VERSION 5.8 ;
BUSBITCHARS "[]" ;
DIVIDERCHAR "/" ;
UNITS
    DATABASE MICRONS 1000 ;
END UNITS

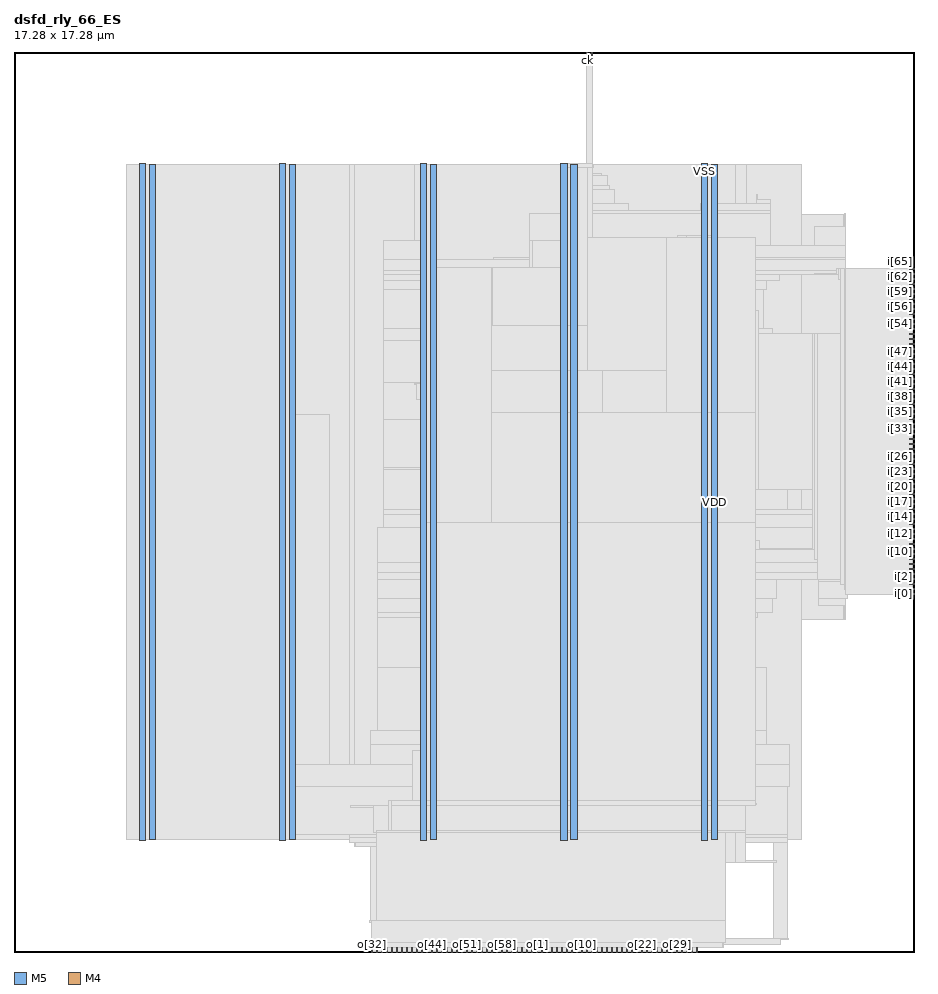
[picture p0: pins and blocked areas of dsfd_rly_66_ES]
MACRO dsfd_rly_66_ES
  FOREIGN dsfd_rly_66_ES 0 0 ;
  CLASS BLOCK ;
  SIZE 17.28 BY 17.28 ;
  PIN ck
    DIRECTION INPUT ;
    USE SIGNAL ;
    PORT
      LAYER M5 ;
        RECT  10.992 17.196 11.016 17.28 ;
    END
  END ck
  PIN i[0]
    DIRECTION INPUT ;
    USE SIGNAL ;
    PORT
      LAYER M4 ;
        RECT  17.196 6.864 17.28 6.888 ;
    END
  END i[0]
  PIN i[10]
    DIRECTION INPUT ;
    USE SIGNAL ;
    PORT
      LAYER M4 ;
        RECT  17.196 7.824 17.28 7.848 ;
    END
  END i[10]
  PIN i[11]
    DIRECTION INPUT ;
    USE SIGNAL ;
    PORT
      LAYER M4 ;
        RECT  17.196 7.92 17.28 7.944 ;
    END
  END i[11]
  PIN i[12]
    DIRECTION INPUT ;
    USE SIGNAL ;
    PORT
      LAYER M4 ;
        RECT  17.196 8.016 17.28 8.04 ;
    END
  END i[12]
  PIN i[13]
    DIRECTION INPUT ;
    USE SIGNAL ;
    PORT
      LAYER M4 ;
        RECT  17.196 8.112 17.28 8.136 ;
    END
  END i[13]
  PIN i[14]
    DIRECTION INPUT ;
    USE SIGNAL ;
    PORT
      LAYER M4 ;
        RECT  17.196 8.208 17.28 8.232 ;
    END
  END i[14]
  PIN i[15]
    DIRECTION INPUT ;
    USE SIGNAL ;
    PORT
      LAYER M4 ;
        RECT  17.196 8.304 17.28 8.328 ;
    END
  END i[15]
  PIN i[16]
    DIRECTION INPUT ;
    USE SIGNAL ;
    PORT
      LAYER M4 ;
        RECT  17.196 8.4 17.28 8.424 ;
    END
  END i[16]
  PIN i[17]
    DIRECTION INPUT ;
    USE SIGNAL ;
    PORT
      LAYER M4 ;
        RECT  17.196 8.496 17.28 8.52 ;
    END
  END i[17]
  PIN i[18]
    DIRECTION INPUT ;
    USE SIGNAL ;
    PORT
      LAYER M4 ;
        RECT  17.196 8.592 17.28 8.616 ;
    END
  END i[18]
  PIN i[19]
    DIRECTION INPUT ;
    USE SIGNAL ;
    PORT
      LAYER M4 ;
        RECT  17.196 8.688 17.28 8.712 ;
    END
  END i[19]
  PIN i[1]
    DIRECTION INPUT ;
    USE SIGNAL ;
    PORT
      LAYER M4 ;
        RECT  17.196 6.96 17.28 6.984 ;
    END
  END i[1]
  PIN i[20]
    DIRECTION INPUT ;
    USE SIGNAL ;
    PORT
      LAYER M4 ;
        RECT  17.196 8.784 17.28 8.808 ;
    END
  END i[20]
  PIN i[21]
    DIRECTION INPUT ;
    USE SIGNAL ;
    PORT
      LAYER M4 ;
        RECT  17.196 8.88 17.28 8.904 ;
    END
  END i[21]
  PIN i[22]
    DIRECTION INPUT ;
    USE SIGNAL ;
    PORT
      LAYER M4 ;
        RECT  17.196 8.976 17.28 9 ;
    END
  END i[22]
  PIN i[23]
    DIRECTION INPUT ;
    USE SIGNAL ;
    PORT
      LAYER M4 ;
        RECT  17.196 9.072 17.28 9.096 ;
    END
  END i[23]
  PIN i[24]
    DIRECTION INPUT ;
    USE SIGNAL ;
    PORT
      LAYER M4 ;
        RECT  17.196 9.168 17.28 9.192 ;
    END
  END i[24]
  PIN i[25]
    DIRECTION INPUT ;
    USE SIGNAL ;
    PORT
      LAYER M4 ;
        RECT  17.196 9.264 17.28 9.288 ;
    END
  END i[25]
  PIN i[26]
    DIRECTION INPUT ;
    USE SIGNAL ;
    PORT
      LAYER M4 ;
        RECT  17.196 9.36 17.28 9.384 ;
    END
  END i[26]
  PIN i[27]
    DIRECTION INPUT ;
    USE SIGNAL ;
    PORT
      LAYER M4 ;
        RECT  17.196 9.456 17.28 9.48 ;
    END
  END i[27]
  PIN i[28]
    DIRECTION INPUT ;
    USE SIGNAL ;
    PORT
      LAYER M4 ;
        RECT  17.196 9.552 17.28 9.576 ;
    END
  END i[28]
  PIN i[29]
    DIRECTION INPUT ;
    USE SIGNAL ;
    PORT
      LAYER M4 ;
        RECT  17.196 9.648 17.28 9.672 ;
    END
  END i[29]
  PIN i[2]
    DIRECTION INPUT ;
    USE SIGNAL ;
    PORT
      LAYER M4 ;
        RECT  17.196 7.056 17.28 7.08 ;
    END
  END i[2]
  PIN i[30]
    DIRECTION INPUT ;
    USE SIGNAL ;
    PORT
      LAYER M4 ;
        RECT  17.196 9.744 17.28 9.768 ;
    END
  END i[30]
  PIN i[31]
    DIRECTION INPUT ;
    USE SIGNAL ;
    PORT
      LAYER M4 ;
        RECT  17.196 9.84 17.28 9.864 ;
    END
  END i[31]
  PIN i[32]
    DIRECTION INPUT ;
    USE SIGNAL ;
    PORT
      LAYER M4 ;
        RECT  17.196 9.936 17.28 9.96 ;
    END
  END i[32]
  PIN i[33]
    DIRECTION INPUT ;
    USE SIGNAL ;
    PORT
      LAYER M4 ;
        RECT  17.196 10.032 17.28 10.056 ;
    END
  END i[33]
  PIN i[34]
    DIRECTION INPUT ;
    USE SIGNAL ;
    PORT
      LAYER M4 ;
        RECT  17.196 10.128 17.28 10.152 ;
    END
  END i[34]
  PIN i[35]
    DIRECTION INPUT ;
    USE SIGNAL ;
    PORT
      LAYER M4 ;
        RECT  17.196 10.224 17.28 10.248 ;
    END
  END i[35]
  PIN i[36]
    DIRECTION INPUT ;
    USE SIGNAL ;
    PORT
      LAYER M4 ;
        RECT  17.196 10.32 17.28 10.344 ;
    END
  END i[36]
  PIN i[37]
    DIRECTION INPUT ;
    USE SIGNAL ;
    PORT
      LAYER M4 ;
        RECT  17.196 10.416 17.28 10.44 ;
    END
  END i[37]
  PIN i[38]
    DIRECTION INPUT ;
    USE SIGNAL ;
    PORT
      LAYER M4 ;
        RECT  17.196 10.512 17.28 10.536 ;
    END
  END i[38]
  PIN i[39]
    DIRECTION INPUT ;
    USE SIGNAL ;
    PORT
      LAYER M4 ;
        RECT  17.196 10.608 17.28 10.632 ;
    END
  END i[39]
  PIN i[3]
    DIRECTION INPUT ;
    USE SIGNAL ;
    PORT
      LAYER M4 ;
        RECT  17.196 7.152 17.28 7.176 ;
    END
  END i[3]
  PIN i[40]
    DIRECTION INPUT ;
    USE SIGNAL ;
    PORT
      LAYER M4 ;
        RECT  17.196 10.704 17.28 10.728 ;
    END
  END i[40]
  PIN i[41]
    DIRECTION INPUT ;
    USE SIGNAL ;
    PORT
      LAYER M4 ;
        RECT  17.196 10.8 17.28 10.824 ;
    END
  END i[41]
  PIN i[42]
    DIRECTION INPUT ;
    USE SIGNAL ;
    PORT
      LAYER M4 ;
        RECT  17.196 10.896 17.28 10.92 ;
    END
  END i[42]
  PIN i[43]
    DIRECTION INPUT ;
    USE SIGNAL ;
    PORT
      LAYER M4 ;
        RECT  17.196 10.992 17.28 11.016 ;
    END
  END i[43]
  PIN i[44]
    DIRECTION INPUT ;
    USE SIGNAL ;
    PORT
      LAYER M4 ;
        RECT  17.196 11.088 17.28 11.112 ;
    END
  END i[44]
  PIN i[45]
    DIRECTION INPUT ;
    USE SIGNAL ;
    PORT
      LAYER M4 ;
        RECT  17.196 11.184 17.28 11.208 ;
    END
  END i[45]
  PIN i[46]
    DIRECTION INPUT ;
    USE SIGNAL ;
    PORT
      LAYER M4 ;
        RECT  17.196 11.28 17.28 11.304 ;
    END
  END i[46]
  PIN i[47]
    DIRECTION INPUT ;
    USE SIGNAL ;
    PORT
      LAYER M4 ;
        RECT  17.196 11.376 17.28 11.4 ;
    END
  END i[47]
  PIN i[48]
    DIRECTION INPUT ;
    USE SIGNAL ;
    PORT
      LAYER M4 ;
        RECT  17.196 11.472 17.28 11.496 ;
    END
  END i[48]
  PIN i[49]
    DIRECTION INPUT ;
    USE SIGNAL ;
    PORT
      LAYER M4 ;
        RECT  17.196 11.568 17.28 11.592 ;
    END
  END i[49]
  PIN i[4]
    DIRECTION INPUT ;
    USE SIGNAL ;
    PORT
      LAYER M4 ;
        RECT  17.196 7.248 17.28 7.272 ;
    END
  END i[4]
  PIN i[50]
    DIRECTION INPUT ;
    USE SIGNAL ;
    PORT
      LAYER M4 ;
        RECT  17.196 11.664 17.28 11.688 ;
    END
  END i[50]
  PIN i[51]
    DIRECTION INPUT ;
    USE SIGNAL ;
    PORT
      LAYER M4 ;
        RECT  17.196 11.76 17.28 11.784 ;
    END
  END i[51]
  PIN i[52]
    DIRECTION INPUT ;
    USE SIGNAL ;
    PORT
      LAYER M4 ;
        RECT  17.196 11.856 17.28 11.88 ;
    END
  END i[52]
  PIN i[53]
    DIRECTION INPUT ;
    USE SIGNAL ;
    PORT
      LAYER M4 ;
        RECT  17.196 11.952 17.28 11.976 ;
    END
  END i[53]
  PIN i[54]
    DIRECTION INPUT ;
    USE SIGNAL ;
    PORT
      LAYER M4 ;
        RECT  17.196 12.048 17.28 12.072 ;
    END
  END i[54]
  PIN i[55]
    DIRECTION INPUT ;
    USE SIGNAL ;
    PORT
      LAYER M4 ;
        RECT  17.196 12.144 17.28 12.168 ;
    END
  END i[55]
  PIN i[56]
    DIRECTION INPUT ;
    USE SIGNAL ;
    PORT
      LAYER M4 ;
        RECT  17.196 12.24 17.28 12.264 ;
    END
  END i[56]
  PIN i[57]
    DIRECTION INPUT ;
    USE SIGNAL ;
    PORT
      LAYER M4 ;
        RECT  17.196 12.336 17.28 12.36 ;
    END
  END i[57]
  PIN i[58]
    DIRECTION INPUT ;
    USE SIGNAL ;
    PORT
      LAYER M4 ;
        RECT  17.196 12.432 17.28 12.456 ;
    END
  END i[58]
  PIN i[59]
    DIRECTION INPUT ;
    USE SIGNAL ;
    PORT
      LAYER M4 ;
        RECT  17.196 12.528 17.28 12.552 ;
    END
  END i[59]
  PIN i[5]
    DIRECTION INPUT ;
    USE SIGNAL ;
    PORT
      LAYER M4 ;
        RECT  17.196 7.344 17.28 7.368 ;
    END
  END i[5]
  PIN i[60]
    DIRECTION INPUT ;
    USE SIGNAL ;
    PORT
      LAYER M4 ;
        RECT  17.196 12.624 17.28 12.648 ;
    END
  END i[60]
  PIN i[61]
    DIRECTION INPUT ;
    USE SIGNAL ;
    PORT
      LAYER M4 ;
        RECT  17.196 12.72 17.28 12.744 ;
    END
  END i[61]
  PIN i[62]
    DIRECTION INPUT ;
    USE SIGNAL ;
    PORT
      LAYER M4 ;
        RECT  17.196 12.816 17.28 12.84 ;
    END
  END i[62]
  PIN i[63]
    DIRECTION INPUT ;
    USE SIGNAL ;
    PORT
      LAYER M4 ;
        RECT  17.196 12.912 17.28 12.936 ;
    END
  END i[63]
  PIN i[64]
    DIRECTION INPUT ;
    USE SIGNAL ;
    PORT
      LAYER M4 ;
        RECT  17.196 13.008 17.28 13.032 ;
    END
  END i[64]
  PIN i[65]
    DIRECTION INPUT ;
    USE SIGNAL ;
    PORT
      LAYER M4 ;
        RECT  17.196 13.104 17.28 13.128 ;
    END
  END i[65]
  PIN i[6]
    DIRECTION INPUT ;
    USE SIGNAL ;
    PORT
      LAYER M4 ;
        RECT  17.196 7.44 17.28 7.464 ;
    END
  END i[6]
  PIN i[7]
    DIRECTION INPUT ;
    USE SIGNAL ;
    PORT
      LAYER M4 ;
        RECT  17.196 7.536 17.28 7.56 ;
    END
  END i[7]
  PIN i[8]
    DIRECTION INPUT ;
    USE SIGNAL ;
    PORT
      LAYER M4 ;
        RECT  17.196 7.632 17.28 7.656 ;
    END
  END i[8]
  PIN i[9]
    DIRECTION INPUT ;
    USE SIGNAL ;
    PORT
      LAYER M4 ;
        RECT  17.196 7.728 17.28 7.752 ;
    END
  END i[9]
  PIN o[0]
    DIRECTION OUTPUT ;
    USE SIGNAL ;
    PORT
      LAYER M5 ;
        RECT  9.936 0 9.96 0.084 ;
    END
  END o[0]
  PIN o[10]
    DIRECTION OUTPUT ;
    USE SIGNAL ;
    PORT
      LAYER M5 ;
        RECT  10.896 0 10.92 0.084 ;
    END
  END o[10]
  PIN o[11]
    DIRECTION OUTPUT ;
    USE SIGNAL ;
    PORT
      LAYER M5 ;
        RECT  10.992 0 11.016 0.084 ;
    END
  END o[11]
  PIN o[12]
    DIRECTION OUTPUT ;
    USE SIGNAL ;
    PORT
      LAYER M5 ;
        RECT  11.088 0 11.112 0.084 ;
    END
  END o[12]
  PIN o[13]
    DIRECTION OUTPUT ;
    USE SIGNAL ;
    PORT
      LAYER M5 ;
        RECT  11.184 0 11.208 0.084 ;
    END
  END o[13]
  PIN o[14]
    DIRECTION OUTPUT ;
    USE SIGNAL ;
    PORT
      LAYER M5 ;
        RECT  11.28 0 11.304 0.084 ;
    END
  END o[14]
  PIN o[15]
    DIRECTION OUTPUT ;
    USE SIGNAL ;
    PORT
      LAYER M5 ;
        RECT  11.376 0 11.4 0.084 ;
    END
  END o[15]
  PIN o[16]
    DIRECTION OUTPUT ;
    USE SIGNAL ;
    PORT
      LAYER M5 ;
        RECT  11.472 0 11.496 0.084 ;
    END
  END o[16]
  PIN o[17]
    DIRECTION OUTPUT ;
    USE SIGNAL ;
    PORT
      LAYER M5 ;
        RECT  11.568 0 11.592 0.084 ;
    END
  END o[17]
  PIN o[18]
    DIRECTION OUTPUT ;
    USE SIGNAL ;
    PORT
      LAYER M5 ;
        RECT  11.664 0 11.688 0.084 ;
    END
  END o[18]
  PIN o[19]
    DIRECTION OUTPUT ;
    USE SIGNAL ;
    PORT
      LAYER M5 ;
        RECT  11.76 0 11.784 0.084 ;
    END
  END o[19]
  PIN o[1]
    DIRECTION OUTPUT ;
    USE SIGNAL ;
    PORT
      LAYER M5 ;
        RECT  10.032 0 10.056 0.084 ;
    END
  END o[1]
  PIN o[20]
    DIRECTION OUTPUT ;
    USE SIGNAL ;
    PORT
      LAYER M5 ;
        RECT  11.856 0 11.88 0.084 ;
    END
  END o[20]
  PIN o[21]
    DIRECTION OUTPUT ;
    USE SIGNAL ;
    PORT
      LAYER M5 ;
        RECT  11.952 0 11.976 0.084 ;
    END
  END o[21]
  PIN o[22]
    DIRECTION OUTPUT ;
    USE SIGNAL ;
    PORT
      LAYER M5 ;
        RECT  12.048 0 12.072 0.084 ;
    END
  END o[22]
  PIN o[23]
    DIRECTION OUTPUT ;
    USE SIGNAL ;
    PORT
      LAYER M5 ;
        RECT  12.144 0 12.168 0.084 ;
    END
  END o[23]
  PIN o[24]
    DIRECTION OUTPUT ;
    USE SIGNAL ;
    PORT
      LAYER M5 ;
        RECT  12.24 0 12.264 0.084 ;
    END
  END o[24]
  PIN o[25]
    DIRECTION OUTPUT ;
    USE SIGNAL ;
    PORT
      LAYER M5 ;
        RECT  12.336 0 12.36 0.084 ;
    END
  END o[25]
  PIN o[26]
    DIRECTION OUTPUT ;
    USE SIGNAL ;
    PORT
      LAYER M5 ;
        RECT  12.432 0 12.456 0.084 ;
    END
  END o[26]
  PIN o[27]
    DIRECTION OUTPUT ;
    USE SIGNAL ;
    PORT
      LAYER M5 ;
        RECT  12.528 0 12.552 0.084 ;
    END
  END o[27]
  PIN o[28]
    DIRECTION OUTPUT ;
    USE SIGNAL ;
    PORT
      LAYER M5 ;
        RECT  12.624 0 12.648 0.084 ;
    END
  END o[28]
  PIN o[29]
    DIRECTION OUTPUT ;
    USE SIGNAL ;
    PORT
      LAYER M5 ;
        RECT  12.72 0 12.744 0.084 ;
    END
  END o[29]
  PIN o[2]
    DIRECTION OUTPUT ;
    USE SIGNAL ;
    PORT
      LAYER M5 ;
        RECT  10.128 0 10.152 0.084 ;
    END
  END o[2]
  PIN o[30]
    DIRECTION OUTPUT ;
    USE SIGNAL ;
    PORT
      LAYER M5 ;
        RECT  12.816 0 12.84 0.084 ;
    END
  END o[30]
  PIN o[31]
    DIRECTION OUTPUT ;
    USE SIGNAL ;
    PORT
      LAYER M5 ;
        RECT  12.912 0 12.936 0.084 ;
    END
  END o[31]
  PIN o[32]
    DIRECTION OUTPUT ;
    USE SIGNAL ;
    PORT
      LAYER M5 ;
        RECT  6.864 0 6.888 0.084 ;
    END
  END o[32]
  PIN o[33]
    DIRECTION OUTPUT ;
    USE SIGNAL ;
    PORT
      LAYER M5 ;
        RECT  6.96 0 6.984 0.084 ;
    END
  END o[33]
  PIN o[34]
    DIRECTION OUTPUT ;
    USE SIGNAL ;
    PORT
      LAYER M5 ;
        RECT  7.056 0 7.08 0.084 ;
    END
  END o[34]
  PIN o[35]
    DIRECTION OUTPUT ;
    USE SIGNAL ;
    PORT
      LAYER M5 ;
        RECT  7.152 0 7.176 0.084 ;
    END
  END o[35]
  PIN o[36]
    DIRECTION OUTPUT ;
    USE SIGNAL ;
    PORT
      LAYER M5 ;
        RECT  7.248 0 7.272 0.084 ;
    END
  END o[36]
  PIN o[37]
    DIRECTION OUTPUT ;
    USE SIGNAL ;
    PORT
      LAYER M5 ;
        RECT  7.344 0 7.368 0.084 ;
    END
  END o[37]
  PIN o[38]
    DIRECTION OUTPUT ;
    USE SIGNAL ;
    PORT
      LAYER M5 ;
        RECT  7.44 0 7.464 0.084 ;
    END
  END o[38]
  PIN o[39]
    DIRECTION OUTPUT ;
    USE SIGNAL ;
    PORT
      LAYER M5 ;
        RECT  7.536 0 7.56 0.084 ;
    END
  END o[39]
  PIN o[3]
    DIRECTION OUTPUT ;
    USE SIGNAL ;
    PORT
      LAYER M5 ;
        RECT  10.224 0 10.248 0.084 ;
    END
  END o[3]
  PIN o[40]
    DIRECTION OUTPUT ;
    USE SIGNAL ;
    PORT
      LAYER M5 ;
        RECT  7.632 0 7.656 0.084 ;
    END
  END o[40]
  PIN o[41]
    DIRECTION OUTPUT ;
    USE SIGNAL ;
    PORT
      LAYER M5 ;
        RECT  7.728 0 7.752 0.084 ;
    END
  END o[41]
  PIN o[42]
    DIRECTION OUTPUT ;
    USE SIGNAL ;
    PORT
      LAYER M5 ;
        RECT  7.824 0 7.848 0.084 ;
    END
  END o[42]
  PIN o[43]
    DIRECTION OUTPUT ;
    USE SIGNAL ;
    PORT
      LAYER M5 ;
        RECT  7.92 0 7.944 0.084 ;
    END
  END o[43]
  PIN o[44]
    DIRECTION OUTPUT ;
    USE SIGNAL ;
    PORT
      LAYER M5 ;
        RECT  8.016 0 8.04 0.084 ;
    END
  END o[44]
  PIN o[45]
    DIRECTION OUTPUT ;
    USE SIGNAL ;
    PORT
      LAYER M5 ;
        RECT  8.112 0 8.136 0.084 ;
    END
  END o[45]
  PIN o[46]
    DIRECTION OUTPUT ;
    USE SIGNAL ;
    PORT
      LAYER M5 ;
        RECT  8.208 0 8.232 0.084 ;
    END
  END o[46]
  PIN o[47]
    DIRECTION OUTPUT ;
    USE SIGNAL ;
    PORT
      LAYER M5 ;
        RECT  8.304 0 8.328 0.084 ;
    END
  END o[47]
  PIN o[48]
    DIRECTION OUTPUT ;
    USE SIGNAL ;
    PORT
      LAYER M5 ;
        RECT  8.4 0 8.424 0.084 ;
    END
  END o[48]
  PIN o[49]
    DIRECTION OUTPUT ;
    USE SIGNAL ;
    PORT
      LAYER M5 ;
        RECT  8.496 0 8.52 0.084 ;
    END
  END o[49]
  PIN o[4]
    DIRECTION OUTPUT ;
    USE SIGNAL ;
    PORT
      LAYER M5 ;
        RECT  10.32 0 10.344 0.084 ;
    END
  END o[4]
  PIN o[50]
    DIRECTION OUTPUT ;
    USE SIGNAL ;
    PORT
      LAYER M5 ;
        RECT  8.592 0 8.616 0.084 ;
    END
  END o[50]
  PIN o[51]
    DIRECTION OUTPUT ;
    USE SIGNAL ;
    PORT
      LAYER M5 ;
        RECT  8.688 0 8.712 0.084 ;
    END
  END o[51]
  PIN o[52]
    DIRECTION OUTPUT ;
    USE SIGNAL ;
    PORT
      LAYER M5 ;
        RECT  8.784 0 8.808 0.084 ;
    END
  END o[52]
  PIN o[53]
    DIRECTION OUTPUT ;
    USE SIGNAL ;
    PORT
      LAYER M5 ;
        RECT  8.88 0 8.904 0.084 ;
    END
  END o[53]
  PIN o[54]
    DIRECTION OUTPUT ;
    USE SIGNAL ;
    PORT
      LAYER M5 ;
        RECT  8.976 0 9 0.084 ;
    END
  END o[54]
  PIN o[55]
    DIRECTION OUTPUT ;
    USE SIGNAL ;
    PORT
      LAYER M5 ;
        RECT  9.072 0 9.096 0.084 ;
    END
  END o[55]
  PIN o[56]
    DIRECTION OUTPUT ;
    USE SIGNAL ;
    PORT
      LAYER M5 ;
        RECT  9.168 0 9.192 0.084 ;
    END
  END o[56]
  PIN o[57]
    DIRECTION OUTPUT ;
    USE SIGNAL ;
    PORT
      LAYER M5 ;
        RECT  9.264 0 9.288 0.084 ;
    END
  END o[57]
  PIN o[58]
    DIRECTION OUTPUT ;
    USE SIGNAL ;
    PORT
      LAYER M5 ;
        RECT  9.36 0 9.384 0.084 ;
    END
  END o[58]
  PIN o[59]
    DIRECTION OUTPUT ;
    USE SIGNAL ;
    PORT
      LAYER M5 ;
        RECT  9.456 0 9.48 0.084 ;
    END
  END o[59]
  PIN o[5]
    DIRECTION OUTPUT ;
    USE SIGNAL ;
    PORT
      LAYER M5 ;
        RECT  10.416 0 10.44 0.084 ;
    END
  END o[5]
  PIN o[60]
    DIRECTION OUTPUT ;
    USE SIGNAL ;
    PORT
      LAYER M5 ;
        RECT  9.552 0 9.576 0.084 ;
    END
  END o[60]
  PIN o[61]
    DIRECTION OUTPUT ;
    USE SIGNAL ;
    PORT
      LAYER M5 ;
        RECT  9.648 0 9.672 0.084 ;
    END
  END o[61]
  PIN o[62]
    DIRECTION OUTPUT ;
    USE SIGNAL ;
    PORT
      LAYER M5 ;
        RECT  9.744 0 9.768 0.084 ;
    END
  END o[62]
  PIN o[63]
    DIRECTION OUTPUT ;
    USE SIGNAL ;
    PORT
      LAYER M5 ;
        RECT  9.84 0 9.864 0.084 ;
    END
  END o[63]
  PIN o[64]
    DIRECTION OUTPUT ;
    USE SIGNAL ;
    PORT
      LAYER M5 ;
        RECT  13.008 0 13.032 0.084 ;
    END
  END o[64]
  PIN o[65]
    DIRECTION OUTPUT ;
    USE SIGNAL ;
    PORT
      LAYER M5 ;
        RECT  13.104 0 13.128 0.084 ;
    END
  END o[65]
  PIN o[6]
    DIRECTION OUTPUT ;
    USE SIGNAL ;
    PORT
      LAYER M5 ;
        RECT  10.512 0 10.536 0.084 ;
    END
  END o[6]
  PIN o[7]
    DIRECTION OUTPUT ;
    USE SIGNAL ;
    PORT
      LAYER M5 ;
        RECT  10.608 0 10.632 0.084 ;
    END
  END o[7]
  PIN o[8]
    DIRECTION OUTPUT ;
    USE SIGNAL ;
    PORT
      LAYER M5 ;
        RECT  10.704 0 10.728 0.084 ;
    END
  END o[8]
  PIN o[9]
    DIRECTION OUTPUT ;
    USE SIGNAL ;
    PORT
      LAYER M5 ;
        RECT  10.8 0 10.824 0.084 ;
    END
  END o[9]
  PIN rs
    DIRECTION INPUT ;
    USE SIGNAL ;
    PORT
      LAYER M5 ;
        RECT  11.088 17.196 11.112 17.28 ;
    END
  END rs
  PIN VDD
    DIRECTION INOUT ;
    USE POWER ;
    PORT
      LAYER M5 ;
        RECT  13.392 2.151 13.512 15.129 ;
        RECT  10.692 2.151 10.812 15.129 ;
        RECT  7.992 2.151 8.112 15.129 ;
        RECT  5.292 2.151 5.412 15.129 ;
        RECT  2.592 2.151 2.712 15.129 ;
    END
  END VDD
  PIN VSS
    DIRECTION INOUT ;
    USE GROUND ;
    PORT
      LAYER M5 ;
        RECT  13.2 2.137 13.32 15.143 ;
        RECT  10.5 2.137 10.62 15.143 ;
        RECT  7.8 2.137 7.92 15.143 ;
        RECT  5.1 2.137 5.22 15.143 ;
        RECT  2.4 2.137 2.52 15.143 ;
    END
  END VSS
  # OT_OBS_CLOSED layer=M5 d_um=1.536 added=5
  OBS
    LAYER RVTN ;
     RECT  2.16 2.16 15.12 2.295 ;
     RECT  2.16 2.565 15.12 2.835 ;
     RECT  2.16 3.105 15.12 3.375 ;
     RECT  2.16 3.645 15.12 3.915 ;
     RECT  2.16 4.185 15.12 4.455 ;
     RECT  2.16 4.725 15.12 4.995 ;
     RECT  2.16 5.265 15.12 5.535 ;
     RECT  2.16 5.805 15.12 6.075 ;
     RECT  2.16 6.345 15.12 6.615 ;
     RECT  2.16 6.885 15.12 7.155 ;
     RECT  2.16 7.425 15.12 7.695 ;
     RECT  2.16 7.965 15.12 8.235 ;
     RECT  2.16 8.505 15.12 8.775 ;
     RECT  2.16 9.045 15.12 9.315 ;
     RECT  2.16 9.585 15.12 9.855 ;
     RECT  2.16 10.125 15.12 10.395 ;
     RECT  2.16 10.665 15.12 10.935 ;
     RECT  2.16 11.205 15.12 11.475 ;
     RECT  2.16 11.745 15.12 12.015 ;
     RECT  2.16 12.285 15.12 12.555 ;
     RECT  2.16 12.825 15.12 13.095 ;
     RECT  2.16 13.365 15.12 13.635 ;
     RECT  2.16 13.905 15.12 14.175 ;
     RECT  2.16 14.445 15.12 14.715 ;
     RECT  2.16 14.985 15.12 15.12 ;
    LAYER RVTP ;
     RECT  2.16 2.295 15.12 2.565 ;
     RECT  2.16 2.835 15.12 3.105 ;
     RECT  2.16 3.375 15.12 3.645 ;
     RECT  2.16 3.915 15.12 4.185 ;
     RECT  2.16 4.455 15.12 4.725 ;
     RECT  2.16 4.995 15.12 5.265 ;
     RECT  2.16 5.535 15.12 5.805 ;
     RECT  2.16 6.075 15.12 6.345 ;
     RECT  2.16 6.615 15.12 6.885 ;
     RECT  2.16 7.155 15.12 7.425 ;
     RECT  2.16 7.695 15.12 7.965 ;
     RECT  2.16 8.235 15.12 8.505 ;
     RECT  2.16 8.775 15.12 9.045 ;
     RECT  2.16 9.315 15.12 9.585 ;
     RECT  2.16 9.855 15.12 10.125 ;
     RECT  2.16 10.395 15.12 10.665 ;
     RECT  2.16 10.935 15.12 11.205 ;
     RECT  2.16 11.475 15.12 11.745 ;
     RECT  2.16 12.015 15.12 12.285 ;
     RECT  2.16 12.555 15.12 12.825 ;
     RECT  2.16 13.095 15.12 13.365 ;
     RECT  2.16 13.635 15.12 13.905 ;
     RECT  2.16 14.175 15.12 14.445 ;
     RECT  2.16 14.715 15.12 14.985 ;
    LAYER M1 ;
     RECT  2.16 2.151 15.12 15.129 ;
    LAYER M2 ;
     RECT  2.16 2.151 6.439 15.129 ;
     RECT  6.439 2.106 6.547 15.129 ;
     RECT  6.547 2.034 7.691 15.129 ;
     RECT  7.691 2.151 13.855 15.129 ;
     RECT  13.855 2.106 14.063 15.129 ;
     RECT  14.063 2.151 15.12 15.129 ;
     RECT  15.12 6.39 15.935 14.166 ;
     RECT  15.935 6.39 15.971 13.086 ;
     RECT  15.935 14.148 15.971 14.166 ;
     RECT  15.971 6.786 16.007 10.926 ;
     RECT  16.007 7.128 16.043 10.926 ;
     RECT  15.971 12.096 16.439 13.086 ;
     RECT  16.043 8.046 16.511 10.926 ;
     RECT  16.043 7.128 16.547 7.146 ;
     RECT  16.511 8.046 17.159 9.954 ;
     RECT  16.439 12.096 17.159 12.924 ;
     RECT  17.159 8.046 17.195 8.064 ;
     RECT  17.159 8.82 17.195 9.108 ;
     RECT  17.159 9.9 17.195 9.918 ;
     RECT  17.159 12.096 17.195 12.114 ;
     RECT  17.159 12.906 17.195 12.924 ;
    LAYER M3 ;
     RECT  8.712 0.091 8.73 0.187 ;
     RECT  14.688 0.139 14.706 0.235 ;
     RECT  12.852 0.283 12.87 0.461 ;
     RECT  6.876 0.475 6.894 0.523 ;
     RECT  8.172 0.187 9.198 0.523 ;
     RECT  6.876 0.523 9.198 0.571 ;
     RECT  10.98 0.091 10.998 1.963 ;
     RECT  11.772 1.723 11.79 1.963 ;
     RECT  10.188 0.091 10.206 2.011 ;
     RECT  10.98 1.963 11.79 2.011 ;
     RECT  6.84 0.571 9.342 2.029 ;
     RECT  6.552 2.029 9.342 2.101 ;
     RECT  13.14 1.771 13.158 2.101 ;
     RECT  14.58 0.235 14.85 2.101 ;
     RECT  6.444 2.101 9.342 2.191 ;
     RECT  10.188 2.011 11.79 2.191 ;
     RECT  13.14 2.101 14.85 2.191 ;
     RECT  5.115 2.143 5.205 2.263 ;
     RECT  6.444 2.191 14.85 2.263 ;
     RECT  2.415 2.143 2.505 2.413 ;
     RECT  5.115 2.263 14.85 3.181 ;
     RECT  5.115 3.181 14.886 3.605 ;
     RECT  6.84 3.605 14.886 3.983 ;
     RECT  6.84 3.983 14.454 4.253 ;
     RECT  6.984 4.253 14.454 5.459 ;
     RECT  6.984 5.459 14.022 6.421 ;
     RECT  6.984 6.421 14.274 6.511 ;
     RECT  15.948 6.385 15.966 6.655 ;
     RECT  6.984 6.511 14.562 6.781 ;
     RECT  15.444 6.655 15.966 6.781 ;
     RECT  15.444 6.781 16.002 7.123 ;
     RECT  6.984 6.781 14.634 7.159 ;
     RECT  15.444 7.123 16.542 7.159 ;
     RECT  6.984 7.159 16.542 7.277 ;
     RECT  6.984 7.277 16.038 7.469 ;
     RECT  6.984 7.469 15.966 8.159 ;
     RECT  7.092 8.159 15.966 8.401 ;
     RECT  17.172 7.819 17.19 8.491 ;
     RECT  7.092 8.401 16.002 8.501 ;
     RECT  15.948 8.501 16.002 8.683 ;
     RECT  17.136 8.491 17.19 8.683 ;
     RECT  15.948 8.683 17.19 9.077 ;
     RECT  7.092 8.501 14.85 9.259 ;
     RECT  15.948 9.077 15.966 9.259 ;
     RECT  7.092 9.259 15.966 9.311 ;
     RECT  17.136 9.077 17.19 9.923 ;
     RECT  15.912 9.311 15.966 9.931 ;
     RECT  17.136 9.923 17.154 9.931 ;
     RECT  15.912 9.931 17.154 9.959 ;
     RECT  7.092 9.311 14.886 10.219 ;
     RECT  15.912 9.959 16.506 10.219 ;
     RECT  5.115 3.605 6.066 10.319 ;
     RECT  7.092 10.219 16.506 10.931 ;
     RECT  7.092 10.931 15.966 11.741 ;
     RECT  15.336 11.741 15.966 11.777 ;
     RECT  15.84 11.777 15.966 11.849 ;
     RECT  17.172 11.563 17.19 11.947 ;
     RECT  7.092 11.741 14.562 11.975 ;
     RECT  15.876 11.849 15.966 12.043 ;
     RECT  17.136 11.947 17.19 12.043 ;
     RECT  7.092 11.975 14.382 12.721 ;
     RECT  15.876 12.043 17.19 12.893 ;
     RECT  7.092 12.721 14.454 12.901 ;
     RECT  15.876 12.893 16.434 12.907 ;
     RECT  17.172 12.893 17.19 12.929 ;
     RECT  7.092 12.901 14.706 13.003 ;
     RECT  15.84 12.907 16.434 13.003 ;
     RECT  7.092 13.003 16.434 13.091 ;
     RECT  7.092 13.091 15.966 13.289 ;
     RECT  9.216 13.289 15.966 13.325 ;
     RECT  9.9 13.325 15.966 13.559 ;
     RECT  7.092 13.289 8.097 13.667 ;
     RECT  15.372 13.559 15.966 13.937 ;
     RECT  9.9 13.559 14.526 14.171 ;
     RECT  15.948 13.937 15.966 14.171 ;
     RECT  10.515 14.171 14.526 14.243 ;
     RECT  10.515 14.243 11.79 14.369 ;
     RECT  13.176 14.243 14.526 14.369 ;
     RECT  14.256 14.369 14.526 14.441 ;
     RECT  14.256 14.441 14.274 14.549 ;
     RECT  10.515 14.369 11.538 14.639 ;
     RECT  10.515 14.639 11.43 14.711 ;
     RECT  2.415 2.413 2.697 14.867 ;
     RECT  5.115 10.319 5.397 14.867 ;
     RECT  7.815 13.667 8.097 14.867 ;
     RECT  13.215 14.369 13.497 14.867 ;
     RECT  10.515 14.711 11.394 14.909 ;
     RECT  10.515 14.909 11.286 14.945 ;
     RECT  10.515 14.945 10.998 15.101 ;
     RECT  2.415 14.867 2.505 15.137 ;
     RECT  5.115 14.867 5.205 15.137 ;
     RECT  7.815 14.867 7.905 15.137 ;
     RECT  10.515 15.101 10.605 15.137 ;
     RECT  13.215 14.867 13.305 15.137 ;
    LAYER M4 ;
     RECT  2.408 2.148 2.512 15.132 ;
     RECT  2.512 2.418 2.704 14.862 ;
     RECT  5.108 2.148 5.212 15.132 ;
     RECT  5.212 2.418 5.404 14.862 ;
     RECT  6.829 0.576 6.865 0.6 ;
     RECT  6.469 2.784 6.901 2.808 ;
     RECT  6.865 0.48 7.117 0.6 ;
     RECT  6.901 2.304 7.189 2.808 ;
     RECT  7.117 0.48 7.513 1.176 ;
     RECT  7.189 2.304 7.513 2.904 ;
     RECT  7.513 0.48 7.657 2.904 ;
     RECT  7.693 10.896 7.729 10.92 ;
     RECT  7.657 0.48 7.808 3.864 ;
     RECT  7.729 10.608 7.808 10.92 ;
     RECT  7.801 12.528 7.808 12.552 ;
     RECT  7.808 0.48 7.912 15.132 ;
     RECT  7.912 0.48 8.005 14.862 ;
     RECT  8.005 0.288 8.104 14.862 ;
     RECT  8.104 0.288 8.156 2.28 ;
     RECT  8.156 0.192 8.531 2.28 ;
     RECT  8.531 1.728 8.533 2.28 ;
     RECT  8.531 0.192 8.657 0.6 ;
     RECT  8.657 0.096 8.741 0.6 ;
     RECT  8.533 1.728 8.819 1.752 ;
     RECT  8.104 3.408 8.993 12.552 ;
     RECT  8.993 10.08 9.133 12.552 ;
     RECT  8.993 3.408 9.205 9.096 ;
     RECT  8.741 0.144 9.353 0.6 ;
     RECT  9.205 2.832 9.443 9.096 ;
     RECT  9.443 2.832 9.589 8.808 ;
     RECT  9.133 10.08 9.889 13.128 ;
     RECT  9.889 10.08 9.961 13.656 ;
     RECT  9.589 2.784 10.165 8.808 ;
     RECT  9.353 0.144 10.177 0.264 ;
     RECT  10.177 0.096 10.357 0.264 ;
     RECT  10.165 2.4 10.508 8.808 ;
     RECT  9.961 9.84 10.508 13.656 ;
     RECT  10.508 2.148 10.612 15.132 ;
     RECT  10.612 2.148 10.693 15.096 ;
     RECT  10.693 2.016 10.789 15.096 ;
     RECT  10.789 1.968 10.804 15.096 ;
     RECT  10.357 0.096 11.053 0.312 ;
     RECT  10.804 15.072 11.123 15.096 ;
     RECT  10.804 1.968 11.717 13.704 ;
     RECT  11.717 1.728 11.795 13.704 ;
     RECT  11.795 3.264 11.809 13.704 ;
     RECT  11.053 0.144 12.037 0.312 ;
     RECT  12.037 0.096 12.565 0.312 ;
     RECT  11.809 9.024 12.733 13.704 ;
     RECT  12.565 0.096 12.841 0.36 ;
     RECT  11.795 1.728 12.877 2.28 ;
     RECT  11.809 3.264 12.877 7.848 ;
     RECT  12.841 0.096 12.901 0.456 ;
     RECT  12.877 1.728 12.901 7.848 ;
     RECT  12.901 0.096 12.985 7.848 ;
     RECT  12.733 9.024 12.985 13.752 ;
     RECT  12.985 0.096 13.091 13.752 ;
     RECT  13.091 1.728 13.208 13.752 ;
     RECT  13.208 1.728 13.312 15.132 ;
     RECT  13.312 1.728 13.504 14.862 ;
     RECT  13.091 0.096 13.619 0.264 ;
     RECT  13.504 1.728 13.667 4.68 ;
     RECT  13.504 5.712 13.817 7.896 ;
     RECT  13.667 1.728 13.859 3.96 ;
     RECT  13.817 6.816 13.859 7.896 ;
     RECT  13.504 8.88 13.889 13.704 ;
     RECT  13.859 1.728 14.051 3.624 ;
     RECT  13.889 8.88 14.069 12.504 ;
     RECT  13.817 5.712 14.077 5.736 ;
     RECT  14.051 2.832 14.213 3.624 ;
     RECT  13.889 13.68 14.243 13.704 ;
     RECT  14.213 2.832 14.257 2.856 ;
     RECT  14.069 8.88 14.285 12.312 ;
     RECT  13.859 7.728 14.321 7.896 ;
     RECT  14.051 1.728 14.645 1.752 ;
     RECT  13.619 0.144 14.717 0.264 ;
     RECT  14.717 0.24 14.861 0.264 ;
     RECT  14.321 7.728 15.325 7.752 ;
     RECT  14.285 8.88 15.325 11.88 ;
     RECT  15.325 7.728 15.361 11.88 ;
     RECT  15.361 7.536 15.433 11.88 ;
     RECT  15.361 13.008 15.793 13.032 ;
     RECT  15.793 13.008 15.829 13.128 ;
     RECT  15.433 7.152 15.865 11.88 ;
     RECT  15.829 12.912 15.865 13.128 ;
     RECT  15.865 7.056 15.937 13.128 ;
     RECT  15.937 6.96 15.973 13.128 ;
     RECT  15.973 6.864 17.244 13.128 ;
    LAYER M5 ;
     RECT  6.864 0.016 13.128 0.085 ;
     RECT  6.864 0.085 13.608 0.181 ;
     RECT  6.864 0.181 13.656 0.611 ;
     RECT  2.4 2.137 2.52 2.151 ;
     RECT  5.1 2.137 5.22 2.151 ;
     RECT  6.96 0.611 13.656 2.293 ;
     RECT  6.96 2.293 14.04 2.339 ;
     RECT  7.248 2.339 14.04 2.821 ;
     RECT  7.248 2.821 14.232 2.915 ;
     RECT  7.8 2.915 14.232 8.243 ;
     RECT  9.168 8.243 14.232 10.355 ;
     RECT  9.168 10.355 11.304 11.171 ;
     RECT  9.168 11.171 11.016 12.035 ;
     RECT  9.168 12.035 9.192 13.139 ;
     RECT  12.528 10.355 14.232 13.715 ;
     RECT  12.912 13.715 13.512 13.763 ;
     RECT  10.5 12.035 11.016 15.061 ;
     RECT  2.4 2.151 2.712 15.129 ;
     RECT  5.1 2.151 5.412 15.129 ;
     RECT  7.8 8.243 8.112 15.129 ;
     RECT  13.2 13.763 13.512 15.129 ;
     RECT  2.4 15.129 2.52 15.143 ;
     RECT  5.1 15.129 5.22 15.143 ;
     RECT  7.8 15.129 7.92 15.143 ;
     RECT  10.5 15.061 11.112 15.143 ;
     RECT  13.2 15.129 13.32 15.143 ;
     RECT  10.992 15.143 11.112 17.232 ;
     RECT  8.112 8.243 9.168 13.139 ;
     RECT  11.304 10.355 12.528 11.171 ;
     RECT  11.016 11.171 12.528 13.715 ;
     RECT  9.192 12.035 10.5 13.139 ;
     RECT  11.016 13.715 11.112 15.061 ;
  END
END dsfd_rly_66_ES
END LIBRARY
